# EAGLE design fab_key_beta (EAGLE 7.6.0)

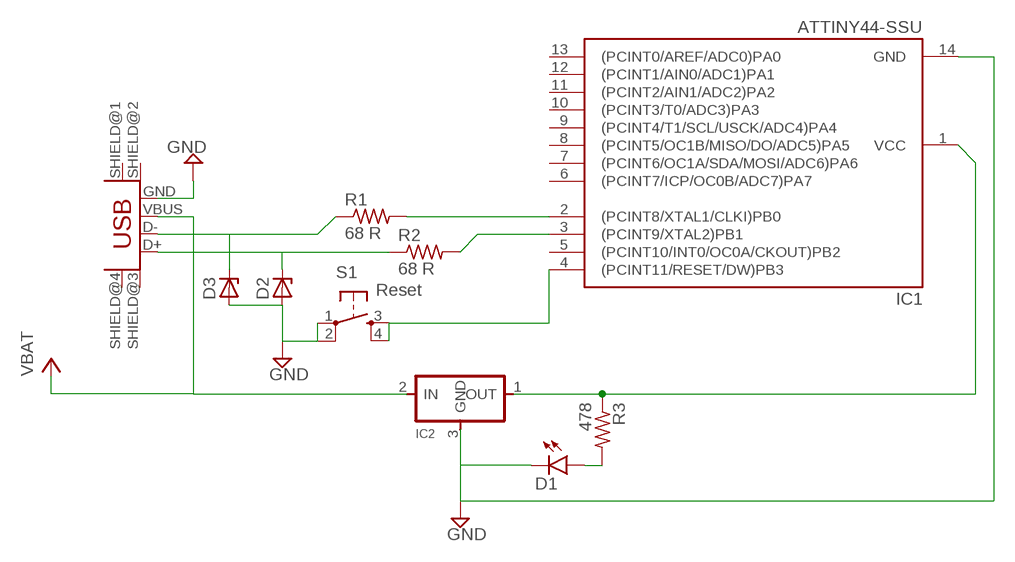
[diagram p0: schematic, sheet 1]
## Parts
D1  LED1206  [LED-1206]
D2  ZENER_DIODESOD123  [SOD123]
D3  ZENER_DIODESOD123  [SOD123]
IC1  ATTINY44-SSU  [SOIC14]
IC2  REGULATORSOT23  [SOT23]
R1  68 R  RES-US1206FAB  [R1206FAB]
R2  68 R  RES-US1206FAB  [R1206FAB]
R3  478  RES-US1206FAB  [R1206FAB]
S1  Reset  6MM_SWITCH6MM_SWITCH  [6MM_SWITCH]
U$1  USB_MINIB  [USB_MINIB]

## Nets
GND: D1.C D2.ANODE D3.ANODE IC1.14(GND) IC2.3(GND) S1.1(P) S1.2(P1) U$1.GND
N$2: IC1.1(VCC) IC2.1(OUT) R3.1
N$3: D3.CATHODE R1.1 U$1.D-
N$4: D2.CATHODE R2.1 U$1.D+
N$5: IC1.2((PCINT8/XTAL1/CLKI)PB0) R1.2
N$6: IC1.3((PCINT9/XTAL2)PB1) R2.2
N$7: IC1.4((PCINT11/RESET/DW)PB3) S1.3(S) S1.4(S1)
N$8: D1.A R3.2
VCC: IC2.2(IN) U$1.VBUS ; supply symbol labelled VBAT
Unconnected: IC1.5((PCINT10/INT0/OC0A/CKOUT)PB2) IC1.6((PCINT7/ICP/OC0B/ADC7)PA7) IC1.7((PCINT6/OC1A/SDA/MOSI/ADC6)PA6) IC1.8((PCINT5/OC1B/MISO/DO/ADC5)PA5) IC1.9((PCINT4/T1/SCL/USCK/ADC4)PA4) IC1.10((PCINT3/T0/ADC3)PA3) IC1.11((PCINT2/AIN1/ADC2)PA2) IC1.12((PCINT1/AIN0/ADC1)PA1) IC1.13((PCINT0/AREF/ADC0)PA0) U$1.SHIELD@1(SHIELD) U$1.SHIELD@2(SHIELD1) U$1.SHIELD@3(SHIELD2) U$1.SHIELD@4(SHIELD3)

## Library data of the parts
D1 = SparkFun-LED:LED: LEDs
D2 D3 = fab:ZENER_DIODE: zener diode
IC1 = fab:ATTINY44
IC2 = fab:REGULATOR
R1-R3 = fab:RES-US: Resistor (US Symbol)
S1 = fab:6MM_SWITCH: OMRON SWITCH
U$1 = fab:USB_MINIB

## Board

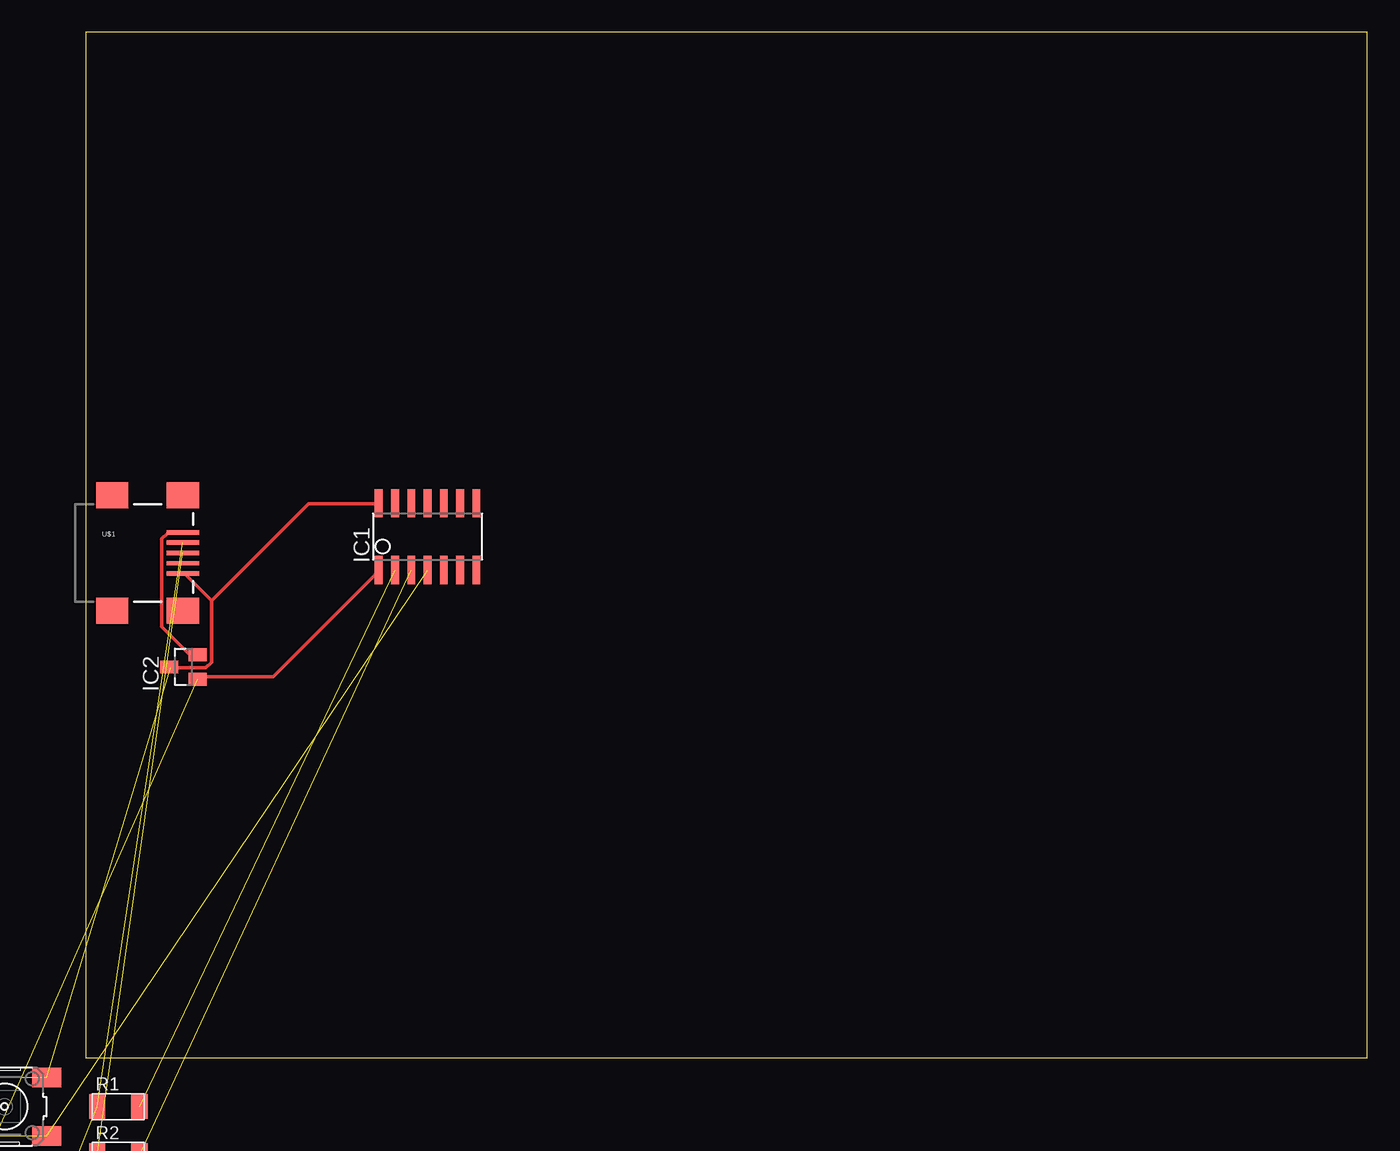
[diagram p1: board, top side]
Size 100 x 80 mm. Coordinates in mm from the lower left corner, seen from the top.
Outline: 0,0 100,0 100,80 0,80 0,0
Copper layers (1*16): Top 0.035mm / dielectric 1.5mm / Bottom 0.035mm
Design rules "default": minimum track width 10mil, minimum drill 24mil, track to track 8mil, track to pad 8mil, pad to pad 8mil, via to via 8mil, smd to smd 8mil, copper to edge 40mil, drill to drill 8mil, minimum pad ring 10mil, minimum via ring 8mil, stop-mask expansion 4mil, vias tented up to drill 0mil, thermal gap 10mil

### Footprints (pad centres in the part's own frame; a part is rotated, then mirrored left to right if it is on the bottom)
LED-1206 = smd 1.2 x 1.4: A -1.5,0; C 1.5,0
SOD123 = smd 1.6 x 0.8: ANODE 1.7,0; CATHODE -1.7,0
SOIC14 = smd 0.61 x 2.21: 1 -3.81,-2.603; 2 -2.54,-2.603; 3 -1.27,-2.603; 4 0,-2.603; 5 1.27,-2.603; 6 2.54,-2.603; 7 3.81,-2.603; 8 3.81,2.603; 9 2.54,2.603; 10 1.27,2.603; 11 0,2.603; 12 -1.27,2.603; 13 -2.54,2.603; 14 -3.81,2.603
SOT23 = smd 1 x 1.4: 1 -0.95,-1.1; 2 0.95,-1.1; 3 0,1.1
R1206FAB = smd 1.27 x 1.905: 1 -1.651,0; 2 1.651,0
6MM_SWITCH = smd 2.286 x 1.524: 1 -3.302,2.286; 2 3.302,2.286; 3 -3.302,-2.286; 4 3.302,-2.286
USB_MINIB = smd 2.5 x 0.35: D+ 3.77,0; D- 3.77,0.8; GND 3.77,-1.6; ID 3.77,-0.8; VBUS 3.77,1.6 | smd 2.5 x 2: SHIELD@1 -1.73,-4.5; SHIELD@2 -1.73,4.5; SHIELD@3 3.77,4.5; SHIELD@4 3.77,-4.5

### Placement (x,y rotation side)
D1  not placed on the board
D2  not placed on the board
D3  not placed on the board
IC1  26.67,40.64 0 top
IC2  7.62,30.48 90 top
R1  not placed on the board
R2  not placed on the board
R3  not placed on the board
S1  not placed on the board
U$1  3.81,39.37 0 top

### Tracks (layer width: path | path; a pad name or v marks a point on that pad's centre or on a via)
GND  (5 unrouted)
  Top 0.254: 9.83,35.66 9.83,30.86 9.37,30.4 6.63,30.4 IC2.3 | 9.83,35.66 7.77,37.72 U$1.GND | 9.83,35.66 17.37,43.2 22.86,43.2 IC1.14
N$2  (1 unrouted)
  Top 0.254: IC2.1 8.91,29.72 14.63,29.72 22.86,37.95 IC1.1
N$3  (2 unrouted)
N$4  (2 unrouted)
N$5  (1 unrouted)
N$6  (1 unrouted)
N$7  (2 unrouted)
N$8  (1 unrouted)
VCC
  Top 0.254: IC2.2 8.69,31.55 8,31.55 5.94,33.6 5.94,40.46 6.4,40.92 7.54,40.92 U$1.VBUS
